! (c) 2009  Infineon Technologies AG, Munich
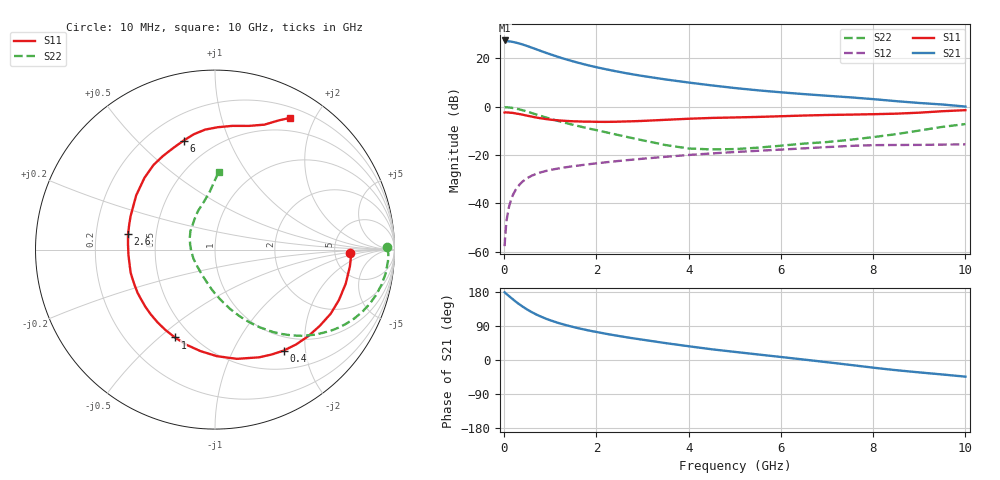
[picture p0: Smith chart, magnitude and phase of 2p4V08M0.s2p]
! Infineon Technologies  Discrete & RF Semiconductors
! BFP420
! VCE =  4.0 V,  IC =  8.0 mA
! Common Emitter S-Parameters:  Nov 2009
# GHz  S  MA  R  50
!  f  S11  S21  S12  S22
! GHz  MAG  ANG  MAG  ANG  MAG  ANG  MAG  ANG
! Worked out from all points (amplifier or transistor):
!   46 points, 10 MHz to 10 GHz, reference 50 ohm
!   highest |S21| = 27.4 dB at 10 MHz (marker M1)
!   |S21| within 3 dB of that: start of sweep to 602.7 MHz
!   unconditionally stable (mu >= 1): start of sweep to 13.88 MHz; 2.584 GHz to end of sweep
!   at 300 MHz: K = 0.20, MSG = 29.6 dB, |S12| = -33.0 dB
!   at 1.7 GHz: K = 0.74, MSG = 20.9 dB, |S12| = -24.2 dB
!   at 10 GHz: K = 1.10, MAG = 5.9 dB, |S12| = -15.6 dB
!   lowest NFmin = 0.79 dB at 900 MHz
!   S11 on the Smith chart (normalised r, x): 10 MHz: 7.05, -0.56; 400 MHz: 0.77, -1.61; 1 GHz: 0.41, -0.56; 2.6 GHz: 0.34, +0.08; 6 GHz: 0.34, +0.69; 10 GHz: 0.33, +1.67
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0.01  0.753 -1.3  23.31 178.8  0.0013 29.5  0.9611 0.7
0.02  0.7585 -2.7  22.61 177.5  0.0019 52.5  0.9658 -1.4
0.1  0.7526 -14.6  22.4 169.2  0.0081 74.7  0.9599 -8.0
0.2  0.737 -29.0  21.63 159.2  0.0156 71.8  0.9319 -15.8
0.3  0.7089 -42.9  20.53 149.6  0.0223 67.3  0.8902 -23.0
0.4  0.6805 -55.8  19.24 141.0  0.0282 62.6  0.8402 -29.4
0.5  0.6486 -67.7  17.87 133.2  0.0332 58.4  0.7873 -35.1
0.6  0.6205 -78.8  16.54 126.2  0.0373 54.6  0.7351 -40.1
0.7  0.5938 -89.0  15.27 119.9  0.0408 51.7  0.6856 -44.5
0.9  0.5538 -106.6  13.02 109.3  0.0465 47.1  0.5989 -51.7
1  0.538 -114.5  12.07 104.8  0.0489 45.5  0.5608 -54.9
1.3  0.5084 -134.6  9.75 93.4  0.055 41.9  0.4678 -62.8
1.7  0.49 -155.7  7.644 81.4  0.062 38.8  0.3772 -71.6
2.2  0.4832 -176.2  5.932 69.4  0.0704 36.1  0.2956 -81.5
2.6  0.4921 169.9  4.997 61.0  0.077 34.0  0.2432 -90.3
3.5  0.5329 145.5  3.643 44.6  0.0916 29.1  0.1602 -116.1
4.5  0.5829 126.0  2.742 28.3  0.1075 22.6  0.1301 -157.4
5.5  0.6116 112.5  2.171 14.6  0.1219 16.0  0.1413 168.8
6  0.6319 106.1  1.974 8.0  0.129 12.8  0.1555 154.6
7  0.6708 94.7  1.676 -5.8  0.1455 5.2  0.1851 132.6
8.5  0.714 74.8  1.295 -26.9  0.1608 -10.0  0.2692 104.0
10  0.8436 60.4  1.002 -43.9  0.166 -20.0  0.4354 87.1
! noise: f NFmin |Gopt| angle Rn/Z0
0.9  0.79  0.08  30  0.13
1.8  1.14  0.06  171  0.12
2.4  1.24  0.1  160  0.13
3  1.32  0.17  -165  0.12
4  1.46  0.32  -132  0.14
5  1.85  0.39  -110  0.25
6  2.3  0.46  -95  0.37
